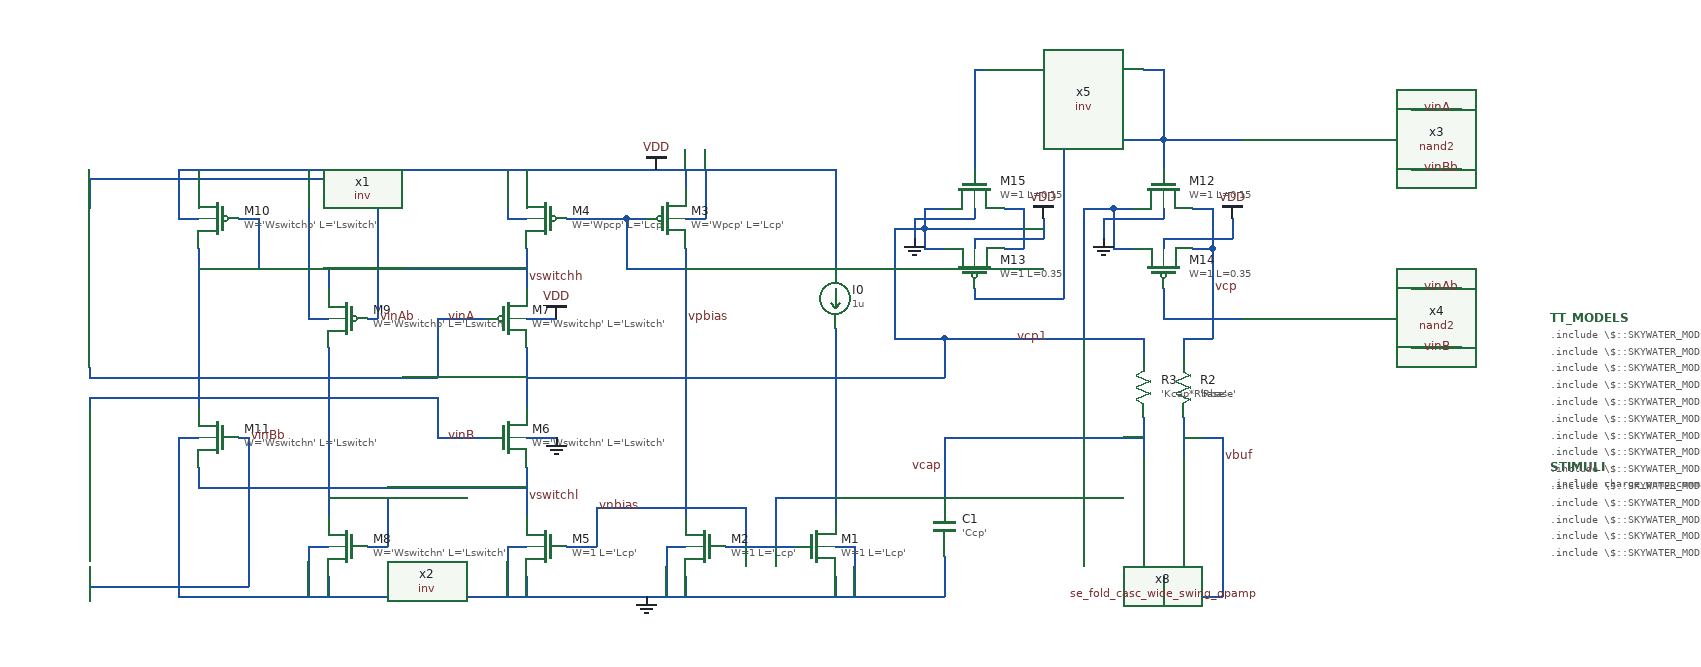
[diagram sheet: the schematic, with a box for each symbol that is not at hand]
v {xschem version=2.9.9 file_version=1.2 }
G {}
K {}
V {}
S {}
E {}
N 420 -190 420 -170 { lab=GND}
N 400 -220 420 -220 { lab=GND}
N 400 -220 400 -170 { lab=GND}
N 420 -550 440 -550 { lab=VDD}
N 420 -600 420 -580 { lab=VDD}
N 440 -600 440 -550 { lab=VDD}
N 460 -220 530 -220 { lab=vnbias}
N 360 -550 360 -500 { lab=vpbias}
N 360 -500 420 -500 { lab=vpbias}
N 360 -550 380 -550 { lab=vpbias}
N 420 -520 420 -250 { lab=vpbias}
N 570 -190 570 -170 { lab=GND}
N 570 -220 590 -220 { lab=GND}
N 590 -220 590 -170 { lab=GND}
N 300 -550 360 -550 { lab=vpbias}
N 240 -550 260 -550 { lab=VDD}
N 240 -600 240 -550 { lab=VDD}
N 260 -600 260 -580 { lab=VDD}
N 260 -190 260 -170 { lab=GND}
N 240 -220 260 -220 { lab=GND}
N 240 -220 240 -170 { lab=GND}
N 480 -260 480 -220 { lab=vnbias}
N 330 -260 480 -260 { lab=vnbias}
N 330 -260 330 -220 { lab=vnbias}
N 300 -220 330 -220 { lab=vnbias}
N 260 -520 260 -480 { lab=vswitchh}
N 260 -420 260 -360 { lab=vcp1}
N 260 -300 260 -250 { lab=vswitchl}
N 260 -330 290 -330 { lab=GND}
N 260 -450 290 -450 { lab=VDD}
N 570 -600 570 -500 { lab=VDD}
N 570 -440 570 -250 { lab=vnbias}
N 510 -270 510 -220 { lab=vnbias}
N 510 -270 570 -270 { lab=vnbias}
N 900 -170 960 -170 { lab=vbuf}
N 900 -190 900 -170 { lab=vbuf}
N 680 -210 680 -170 { lab=GND}
N 920 -330 960 -330 { lab=vbuf}
N 960 -330 960 -170 { lab=vbuf}
N 680 -330 680 -270 { lab=vcap}
N 880 -350 880 -310 { lab=vcap}
N 920 -350 920 -310 { lab=vbuf}
N 260 -390 680 -390 { lab=vcp1}
N 880 -430 880 -410 { lab=vcp1}
N 920 -430 920 -410 { lab=vcp}
N 40 -450 60 -450 { lab=VDD}
N 100 -220 120 -220 { lab=#net1}
N 120 -270 120 -220 { lab=#net1}
N 60 -270 120 -270 { lab=#net1}
N -70 -300 -70 -280 { lab=vswitchl}
N -90 -330 -70 -330 { lab=GND}
N -90 -550 -70 -550 { lab=VDD}
N -90 -600 -90 -550 { lab=VDD}
N -70 -600 -70 -580 { lab=VDD}
N 40 -220 60 -220 { lab=GND}
N 60 -190 60 -170 { lab=GND}
N 40 -220 40 -170 { lab=GND}
N -30 -550 -10 -550 { lab=#net2}
N -10 -550 -10 -500 { lab=#net2}
N -70 -500 -10 -500 { lab=#net2}
N 60 -500 260 -500 { lab=vswitchh}
N -70 -280 260 -280 { lab=vswitchl}
N 200 -450 220 -450 { lab=vinA}
N 100 -450 110 -450 { lab=vinAb}
N 200 -330 220 -330 { lab=vinB}
N -30 -330 -20 -330 { lab=vinBb}
N -90 -170 680 -170 { lab=GND}
N -90 -600 570 -600 { lab=VDD}
N -180 -590 -180 -560 { lab=vinAb}
N -180 -590 110 -590 { lab=vinAb}
N -180 -200 -180 -180 { lab=vinBb}
N -180 -180 -20 -180 { lab=vinBb}
N -180 -400 -180 -390 { lab=vinA}
N -180 -390 170 -390 { lab=vinA}
N 170 -450 170 -390 { lab=vinA}
N 170 -450 200 -450 { lab=vinA}
N -180 -370 -180 -360 { lab=vinB}
N -180 -370 170 -370 { lab=vinB}
N 170 -370 170 -330 { lab=vinB}
N 170 -330 200 -330 { lab=vinB}
N 60 -500 60 -480 { lab=vswitchh}
N 60 -420 60 -250 { lab=#net1}
N 40 -600 40 -450 { lab=VDD}
N 110 -590 110 -450 { lab=vinAb}
N -90 -330 -90 -170 { lab=GND}
N -70 -520 -70 -360 { lab=#net2}
N -20 -330 -20 -180 { lab=vinBb}
N 680 -330 710 -330 { lab=vcap}
N 850 -560 850 -540 { lab=vcp1}
N 850 -560 870 -560 { lab=vcp1}
N 850 -540 850 -520 { lab=vcp1}
N 850 -520 870 -520 { lab=vcp1}
N 930 -560 950 -560 { lab=vcp}
N 950 -560 950 -520 { lab=vcp}
N 930 -520 950 -520 { lab=vcp}
N 810 -330 880 -330 { lab=vcap}
N 680 -430 880 -430 { lab=vcp1}
N 900 -480 900 -450 { lab=#net3}
N 900 -630 900 -600 { lab=#net4}
N 900 -530 900 -520 { lab=VDD}
N 900 -560 900 -550 { lab=GND}
N 900 -530 970 -530 { lab=VDD}
N 970 -550 970 -530 { lab=VDD}
N 840 -550 900 -550 { lab=GND}
N 840 -550 840 -530 { lab=GND}
N 820 -560 850 -560 { lab=vcp1}
N 710 -330 810 -330 { lab=vcap}
N 680 -430 680 -390 { lab=vcp1}
N 820 -560 820 -430 { lab=vcp1}
N 920 -430 950 -430 { lab=vcp}
N 950 -520 950 -430 { lab=vcp}
N 900 -450 980 -450 { lab=#net3}
N 900 -630 980 -630 { lab=#net4}
N 1150 -660 1200 -660 { lab=vinA}
N 1150 -600 1200 -600 { lab=vinBb}
N 1150 -480 1200 -480 { lab=vinAb}
N 1150 -420 1200 -420 { lab=vinB}
N 660 -560 660 -540 { lab=vcp1}
N 660 -560 680 -560 { lab=vcp1}
N 660 -540 660 -520 { lab=vcp1}
N 660 -520 680 -520 { lab=vcp1}
N 740 -560 760 -560 { lab=vcp1}
N 760 -560 760 -520 { lab=vcp1}
N 740 -520 760 -520 { lab=vcp1}
N 710 -530 710 -520 { lab=VDD}
N 710 -560 710 -550 { lab=GND}
N 710 -530 780 -530 { lab=VDD}
N 780 -550 780 -530 { lab=VDD}
N 650 -550 710 -550 { lab=GND}
N 650 -550 650 -530 { lab=GND}
N 900 -700 900 -630 { lab=#net4}
N 880 -700 900 -700 { lab=#net4}
N 800 -630 900 -630 { lab=#net4}
N 800 -630 800 -470 { lab=#net4}
N 710 -470 800 -470 { lab=#net4}
N 710 -480 710 -470 { lab=#net4}
N 710 -700 720 -700 { lab=#net5}
N 710 -700 710 -600 { lab=#net5}
N 660 -540 760 -540 { lab=vcp1}
N 630 -540 660 -540 { lab=vcp1}
N 630 -430 680 -430 { lab=vcp1}
N 630 -540 630 -430 { lab=vcp1}
C {devices/title.sym} 160 -30 0 0 {name=l1 author="Nikhil Poole"}
C {devices/code.sym} 1290 -300 0 0 {name=STIMULI 
only_toplevel=true
place=end
value=".include charge_pump_commands.spice"}
C {devices/code.sym} 1290 -450 0 0 {name=TT_MODELS
only_toplevel=true
format="tcleval( @value )"
value="
.include \\\\$::SKYWATER_MODELS\\\\/cells/nfet_01v8/sky130_fd_pr__nfet_01v8__tt.corner.spice
.include \\\\$::SKYWATER_MODELS\\\\/cells/nfet_01v8_lvt/sky130_fd_pr__nfet_01v8_lvt__tt.corner.spice
.include \\\\$::SKYWATER_MODELS\\\\/cells/pfet_01v8/sky130_fd_pr__pfet_01v8__tt.corner.spice
.include \\\\$::SKYWATER_MODELS\\\\/cells/nfet_03v3_nvt/sky130_fd_pr__nfet_03v3_nvt__tt.corner.spice
.include \\\\$::SKYWATER_MODELS\\\\/cells/nfet_05v0_nvt/sky130_fd_pr__nfet_05v0_nvt__tt.corner.spice
.include \\\\$::SKYWATER_MODELS\\\\/cells/esd_nfet_01v8/sky130_fd_pr__esd_nfet_01v8__tt.corner.spice
.include \\\\$::SKYWATER_MODELS\\\\/cells/pfet_01v8_lvt/sky130_fd_pr__pfet_01v8_lvt__tt.corner.spice
.include \\\\$::SKYWATER_MODELS\\\\/cells/pfet_01v8_hvt/sky130_fd_pr__pfet_01v8_hvt__tt.corner.spice
.include \\\\$::SKYWATER_MODELS\\\\/cells/esd_pfet_g5v0d10v5/sky130_fd_pr__esd_pfet_g5v0d10v5__tt.corner.spice
.include \\\\$::SKYWATER_MODELS\\\\/cells/pfet_g5v0d10v5/sky130_fd_pr__pfet_g5v0d10v5__tt.corner.spice
.include \\\\$::SKYWATER_MODELS\\\\/cells/pfet_g5v0d16v0/sky130_fd_pr__pfet_g5v0d16v0__tt.corner.spice
.include \\\\$::SKYWATER_MODELS\\\\/cells/nfet_g5v0d10v5/sky130_fd_pr__nfet_g5v0d10v5__tt.corner.spice
.include \\\\$::SKYWATER_MODELS\\\\/cells/nfet_g5v0d16v0/sky130_fd_pr__nfet_g5v0d16v0__tt_discrete.corner.spice
.include \\\\$::SKYWATER_MODELS\\\\/cells/esd_nfet_g5v0d10v5/sky130_fd_pr__esd_nfet_g5v0d10v5__tt.corner.spice
.include \\\\$::SKYWATER_MODELS\\\\/models/corners/tt/nonfet.spice
* Standard cells
.include \\\\$::SKYWATER_STDCELLS\\\\/cells/inv/sky130_fd_sc_hd__inv_4.spice
* Mismatch parameters
.include \\\\$::SKYWATER_MODELS\\\\/cells/nfet_01v8/sky130_fd_pr__nfet_01v8__mismatch.corner.spice
.include \\\\$::SKYWATER_MODELS\\\\/cells/pfet_01v8/sky130_fd_pr__pfet_01v8__mismatch.corner.spice
.include \\\\$::SKYWATER_MODELS\\\\/cells/nfet_01v8_lvt/sky130_fd_pr__nfet_01v8_lvt__mismatch.corner.spice
.include \\\\$::SKYWATER_MODELS\\\\/cells/pfet_01v8_lvt/sky130_fd_pr__pfet_01v8_lvt__mismatch.corner.spice
.include \\\\$::SKYWATER_MODELS\\\\/cells/pfet_01v8_hvt/sky130_fd_pr__pfet_01v8_hvt__mismatch.corner.spice
.include \\\\$::SKYWATER_MODELS\\\\/cells/nfet_g5v0d10v5/sky130_fd_pr__nfet_g5v0d10v5__mismatch.corner.spice
.include \\\\$::SKYWATER_MODELS\\\\/cells/pfet_g5v0d10v5/sky130_fd_pr__pfet_g5v0d10v5__mismatch.corner.spice
.include \\\\$::SKYWATER_MODELS\\\\/cells/nfet_05v0_nvt/sky130_fd_pr__nfet_05v0_nvt__mismatch.corner.spice
.include \\\\$::SKYWATER_MODELS\\\\/cells/nfet_03v3_nvt/sky130_fd_pr__nfet_03v3_nvt__mismatch.corner.spice
* Resistor\\\\$::SKYWATER_MODELS\\\\/Capacitor
.include \\\\$::SKYWATER_MODELS\\\\/models/r+c/res_typical__cap_typical.spice
.include \\\\$::SKYWATER_MODELS\\\\/models/r+c/res_typical__cap_typical__lin.spice
* Special cells
.include \\\\$::SKYWATER_MODELS\\\\/models/corners/tt/specialized_cells.spice
* All models
.include \\\\$::SKYWATER_MODELS\\\\/models/all.spice
* Corner
.include \\\\$::SKYWATER_MODELS\\\\/models/corners/tt/rf.spice
"}
C {devices/lab_wire.sym} 330 -260 0 1 {name=l2 sig_type=std_logic lab=vnbias}
C {devices/lab_wire.sym} 420 -450 0 1 {name=l8 sig_type=std_logic lab=vpbias}
C {devices/isource.sym} 570 -470 0 1 {name=I0 value=1u}
C {sky130_fd_pr/nfet_01v8.sym} 550 -220 0 0 {name=M1
L='Lcp'
W=1
nf=1 
mult=100
ad="'int((nf+1)/2) * W/nf * 0.29'" 
pd="'2*int((nf+1)/2) * (W/nf + 0.29)'"
as="'int((nf+2)/2) * W/nf * 0.29'" 
ps="'2*int((nf+2)/2) * (W/nf + 0.29)'"
nrd="'0.29 / W'" nrs="'0.29 / W'"
sa=0 sb=0 sd=0
model=nfet_01v8
spiceprefix=X
}
C {sky130_fd_pr/nfet_01v8.sym} 440 -220 0 1 {name=M2
L='Lcp'
W=1
nf=1 
mult=1
ad="'int((nf+1)/2) * W/nf * 0.29'" 
pd="'2*int((nf+1)/2) * (W/nf + 0.29)'"
as="'int((nf+2)/2) * W/nf * 0.29'" 
ps="'2*int((nf+2)/2) * (W/nf + 0.29)'"
nrd="'0.29 / W'" nrs="'0.29 / W'"
sa=0 sb=0 sd=0
model=nfet_01v8
spiceprefix=X
}
C {sky130_fd_pr/nfet_01v8.sym} 280 -220 0 1 {name=M5
L='Lcp'
W=1
nf=1 
mult=1
ad="'int((nf+1)/2) * W/nf * 0.29'" 
pd="'2*int((nf+1)/2) * (W/nf + 0.29)'"
as="'int((nf+2)/2) * W/nf * 0.29'" 
ps="'2*int((nf+2)/2) * (W/nf + 0.29)'"
nrd="'0.29 / W'" nrs="'0.29 / W'"
sa=0 sb=0 sd=0
model=nfet_01v8
spiceprefix=X
}
C {sky130_fd_pr/nfet_01v8_lvt.sym} 240 -330 0 0 {name=M6
L='Lswitch'
W='Wswitchn'
nf=1
mult=1
ad="'int((nf+1)/2) * W/nf * 0.29'" 
pd="'2*int((nf+1)/2) * (W/nf + 0.29)'"
as="'int((nf+2)/2) * W/nf * 0.29'" 
ps="'2*int((nf+2)/2) * (W/nf + 0.29)'"
nrd="'0.29 / W'" nrs="'0.29 / W'"
sa=0 sb=0 sd=0
model=nfet_01v8_lvt
spiceprefix=X
}
C {sky130_fd_pr/pfet_01v8_lvt.sym} 240 -450 0 0 {name=M7
L='Lswitch'
W='Wswitchp'
nf=1
mult=1
ad="'int((nf+1)/2) * W/nf * 0.29'" 
pd="'2*int((nf+1)/2) * (W/nf + 0.29)'"
as="'int((nf+2)/2) * W/nf * 0.29'" 
ps="'2*int((nf+2)/2) * (W/nf + 0.29)'"
nrd="'0.29 / W'" nrs="'0.29 / W'"
sa=0 sb=0 sd=0
model=pfet_01v8_lvt
spiceprefix=X
}
C {devices/gnd.sym} 290 -330 0 0 {name=l5 lab=GND}
C {devices/gnd.sym} 380 -170 0 0 {name=l6 lab=GND}
C {devices/vdd.sym} 390 -600 0 0 {name=l7 lab=VDD}
C {devices/vdd.sym} 290 -450 0 0 {name=l9 lab=VDD}
C {devices/lab_wire.sym} 950 -480 0 1 {name=l10 sig_type=std_logic lab=vcp}
C {devices/lab_wire.sym} 210 -450 0 0 {name=l3 sig_type=std_logic lab=vinA}
C {sky130_fd_pr/pfet_01v8.sym} 280 -550 0 1 {name=M4
L='Lcp'
W='Wpcp'
nf=1
mult='Mpcp'
ad="'int((nf+1)/2) * W/nf * 0.29'" 
pd="'2*int((nf+1)/2) * (W/nf + 0.29)'"
as="'int((nf+2)/2) * W/nf * 0.29'" 
ps="'2*int((nf+2)/2) * (W/nf + 0.29)'"
nrd="'0.29 / W'" nrs="'0.29 / W'"
sa=0 sb=0 sd=0
model=pfet_01v8
spiceprefix=X
}
C {sky130_fd_pr/pfet_01v8.sym} 400 -550 0 0 {name=M3
L='Lcp'
W='Wpcp'
nf=1
mult='Mpcp'
ad="'int((nf+1)/2) * W/nf * 0.29'" 
pd="'2*int((nf+1)/2) * (W/nf + 0.29)'"
as="'int((nf+2)/2) * W/nf * 0.29'" 
ps="'2*int((nf+2)/2) * (W/nf + 0.29)'"
nrd="'0.29 / W'" nrs="'0.29 / W'"
sa=0 sb=0 sd=0
model=pfet_01v8
spiceprefix=X
}
C {devices/capa.sym} 680 -240 0 0 {name=C1
m=1
value='Ccp'
footprint=1206
device="ceramic capacitor"}
C {devices/res.sym} 920 -380 0 0 {name=R2
value='Rbase'
footprint=1206
device=resistor
m=1}
C {devices/res.sym} 880 -380 0 1 {name=R3
value='Kcap*Rbase'
footprint=1206
device=resistor
m=1}
C {devices/lab_wire.sym} 680 -300 0 0 {name=l17 sig_type=std_logic lab=vcap}
C {devices/lab_wire.sym} 960 -310 2 0 {name=l18 sig_type=std_logic lab=vbuf}
C {/home/users/nhpoole/ee272b/ee272b_mixed_signal_mmwave_accelerator/designs/se_fold_casc_wide_swing_opamp.sym} 900 -260 3 1 {name=x8}
C {devices/lab_wire.sym} 210 -330 0 0 {name=l4 sig_type=std_logic lab=vinB}
C {devices/lab_wire.sym} 260 -490 0 1 {name=l11 sig_type=std_logic lab=vswitchh}
C {devices/lab_wire.sym} 260 -270 0 1 {name=l12 sig_type=std_logic lab=vswitchl}
C {sky130_fd_pr/nfet_01v8.sym} 80 -220 0 1 {name=M8
L='Lswitch'
W='Wswitchn'
nf=1 
mult=1
ad="'int((nf+1)/2) * W/nf * 0.29'" 
pd="'2*int((nf+1)/2) * (W/nf + 0.29)'"
as="'int((nf+2)/2) * W/nf * 0.29'" 
ps="'2*int((nf+2)/2) * (W/nf + 0.29)'"
nrd="'0.29 / W'" nrs="'0.29 / W'"
sa=0 sb=0 sd=0
model=nfet_01v8
spiceprefix=X
}
C {sky130_fd_pr/pfet_01v8.sym} 80 -450 0 1 {name=M9
L='Lswitch'
W='Wswitchp'
nf=1
mult=1
ad="'int((nf+1)/2) * W/nf * 0.29'" 
pd="'2*int((nf+1)/2) * (W/nf + 0.29)'"
as="'int((nf+2)/2) * W/nf * 0.29'" 
ps="'2*int((nf+2)/2) * (W/nf + 0.29)'"
nrd="'0.29 / W'" nrs="'0.29 / W'"
sa=0 sb=0 sd=0
model=pfet_01v8
spiceprefix=X
}
C {devices/lab_wire.sym} 110 -450 0 1 {name=l13 sig_type=std_logic lab=vinAb}
C {sky130_fd_pr/pfet_01v8.sym} -50 -550 0 1 {name=M10
L='Lswitch'
W='Wswitchp'
nf=1
mult=1
ad="'int((nf+1)/2) * W/nf * 0.29'" 
pd="'2*int((nf+1)/2) * (W/nf + 0.29)'"
as="'int((nf+2)/2) * W/nf * 0.29'" 
ps="'2*int((nf+2)/2) * (W/nf + 0.29)'"
nrd="'0.29 / W'" nrs="'0.29 / W'"
sa=0 sb=0 sd=0
model=pfet_01v8
spiceprefix=X
}
C {sky130_fd_pr/nfet_01v8.sym} -50 -330 0 1 {name=M11
L='Lswitch'
W='Wswitchn'
nf=1 
mult=1
ad="'int((nf+1)/2) * W/nf * 0.29'" 
pd="'2*int((nf+1)/2) * (W/nf + 0.29)'"
as="'int((nf+2)/2) * W/nf * 0.29'" 
ps="'2*int((nf+2)/2) * (W/nf + 0.29)'"
nrd="'0.29 / W'" nrs="'0.29 / W'"
sa=0 sb=0 sd=0
model=nfet_01v8
spiceprefix=X
}
C {devices/lab_wire.sym} -20 -330 0 1 {name=l14 sig_type=std_logic lab=vinBb}
C {/home/users/nhpoole/ee272b/ee272b_mixed_signal_mmwave_accelerator/designs/inv.sym} -180 -450 3 0 {name=x1 M=1}
C {/home/users/nhpoole/ee272b/ee272b_mixed_signal_mmwave_accelerator/designs/inv.sym} -180 -310 1 0 {name=x2 M=1}
C {devices/vdd.sym} 970 -550 0 0 {name=l19 lab=VDD}
C {devices/gnd.sym} 840 -530 0 1 {name=l20 lab=GND}
C {sky130_fd_pr/pfet_01v8_lvt.sym} 900 -500 3 0 {name=M14
L=0.35
W=1
nf=1
mult=1
ad="'int((nf+1)/2) * W/nf * 0.29'" 
pd="'2*int((nf+1)/2) * (W/nf + 0.29)'"
as="'int((nf+2)/2) * W/nf * 0.29'" 
ps="'2*int((nf+2)/2) * (W/nf + 0.29)'"
nrd="'0.29 / W'" nrs="'0.29 / W'"
sa=0 sb=0 sd=0
model=pfet_01v8_lvt
spiceprefix=X
}
C {sky130_fd_pr/nfet_01v8_lvt.sym} 900 -580 1 0 {name=M12
L=0.15
W=1
nf=1
mult=1
ad="'int((nf+1)/2) * W/nf * 0.29'" 
pd="'2*int((nf+1)/2) * (W/nf + 0.29)'"
as="'int((nf+2)/2) * W/nf * 0.29'" 
ps="'2*int((nf+2)/2) * (W/nf + 0.29)'"
nrd="'0.29 / W'" nrs="'0.29 / W'"
sa=0 sb=0 sd=0
model=nfet_01v8_lvt
spiceprefix=X
}
C {devices/lab_wire.sym} 750 -430 0 1 {name=l21 sig_type=std_logic lab=vcp1}
C {/home/users/nhpoole/ee272b/ee272b_mixed_signal_mmwave_accelerator/designs/nand2.sym} 1080 -630 0 1 {name=x3 M=1}
C {/home/users/nhpoole/ee272b/ee272b_mixed_signal_mmwave_accelerator/designs/nand2.sym} 1080 -450 0 1 {name=x4 M=1}
C {devices/lab_wire.sym} 1160 -660 0 1 {name=l22 sig_type=std_logic lab=vinA}
C {devices/lab_wire.sym} 1160 -480 0 1 {name=l23 sig_type=std_logic lab=vinAb}
C {devices/lab_wire.sym} 1160 -420 0 1 {name=l24 sig_type=std_logic lab=vinB}
C {devices/lab_wire.sym} 1160 -600 0 1 {name=l25 sig_type=std_logic lab=vinBb}
C {devices/vdd.sym} 780 -550 0 0 {name=l16 lab=VDD}
C {devices/gnd.sym} 650 -530 0 1 {name=l26 lab=GND}
C {sky130_fd_pr/pfet_01v8_lvt.sym} 710 -500 3 0 {name=M13
L=0.35
W=1
nf=1
mult=1
ad="'int((nf+1)/2) * W/nf * 0.29'" 
pd="'2*int((nf+1)/2) * (W/nf + 0.29)'"
as="'int((nf+2)/2) * W/nf * 0.29'" 
ps="'2*int((nf+2)/2) * (W/nf + 0.29)'"
nrd="'0.29 / W'" nrs="'0.29 / W'"
sa=0 sb=0 sd=0
model=pfet_01v8_lvt
spiceprefix=X
}
C {sky130_fd_pr/nfet_01v8_lvt.sym} 710 -580 1 0 {name=M15
L=0.15
W=1
nf=1
mult=1
ad="'int((nf+1)/2) * W/nf * 0.29'" 
pd="'2*int((nf+1)/2) * (W/nf + 0.29)'"
as="'int((nf+2)/2) * W/nf * 0.29'" 
ps="'2*int((nf+2)/2) * (W/nf + 0.29)'"
nrd="'0.29 / W'" nrs="'0.29 / W'"
sa=0 sb=0 sd=0
model=nfet_01v8_lvt
spiceprefix=X
}
C {/home/users/nhpoole/ee272b/ee272b_mixed_signal_mmwave_accelerator/designs/inv.sym} 830 -700 2 0 {name=x5 M=1}
